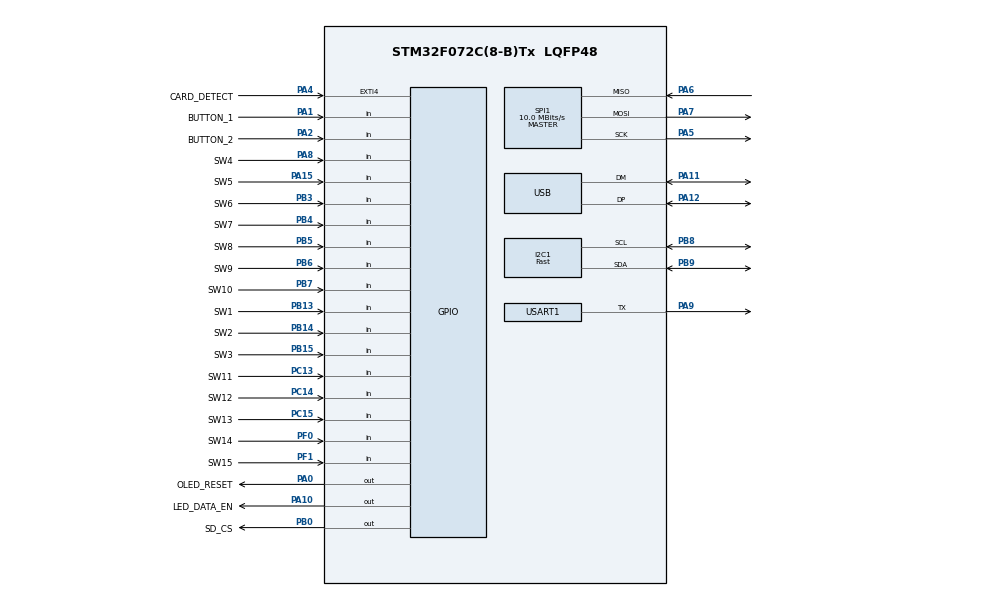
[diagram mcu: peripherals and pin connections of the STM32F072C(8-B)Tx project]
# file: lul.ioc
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FATFS._CODE_PAGE=1252
FATFS._FS_LOCK=0
FATFS._FS_NORTC=1
FATFS._FS_TINY=1
FATFS._LFN_UNICODE=0
FATFS._MAX_LFN=32
FATFS._USE_FIND=0
FATFS._USE_LFN=3
FATFS._USE_MKFS=0
FREERTOS.HEAP_NUMBER=1
FREERTOS.MEMORY_ALLOCATION=0
FREERTOS.Tasks01=kb_scan,0,256,kb_scan_task,Default,NULL,Dynamic,NULL,NULL
FREERTOS.configMINIMAL_STACK_SIZE=128
FREERTOS.configTOTAL_HEAP_SIZE=5100
I2C1.I2C_Speed_Mode=I2C_Fast
I2C1.Speed=400
I2C1.Timing=0x0000020B
IWDG.Prescaler=IWDG_PRESCALER_32
IWDG.Reload=4095
IWDG.Window=4095
Mcu.Family=STM32F0
Mcu.Name=STM32F072C(8-B)Tx
Mcu.Package=LQFP48
NVIC.EXTI4_15_IRQn=true\:3\:0\:false\:false\:true\:true\:true
NVIC.TIM6_DAC_IRQn=true\:0\:0\:false\:false\:true\:false\:true
NVIC.TimeBase=TIM6_DAC_IRQn
NVIC.TimeBaseIP=TIM6
NVIC.USB_IRQn=true\:3\:0\:false\:false\:true\:true\:true
PA0.GPIO_Label=OLED_RESET
PA0.PinState=GPIO_PIN_RESET
PA0.Signal=GPIO_Output
PA1.GPIO_Label=BUTTON_1
PA1.GPIO_PuPd=GPIO_PULLUP
PA1.Signal=GPIO_Input
PA10.GPIO_Label=LED_DATA_EN
PA10.Signal=GPIO_Output
PA11.Mode=Device
PA11.Signal=USB_DM
PA12.Mode=Device
PA12.Signal=USB_DP
PA13.Mode=Serial_Wire
PA13.Signal=SYS_SWDIO
PA14.Mode=Serial_Wire
PA14.Signal=SYS_SWCLK
PA15.GPIO_Label=SW5
PA15.GPIO_PuPd=GPIO_PULLUP
PA15.Signal=GPIO_Input
PA2.GPIO_Label=BUTTON_2
PA2.GPIO_PuPd=GPIO_PULLUP
PA2.Signal=GPIO_Input
PA4.GPIO_Label=CARD_DETECT
PA4.GPIO_ModeDefaultEXTI=GPIO_MODE_IT_RISING_FALLING
PA4.GPIO_PuPd=GPIO_PULLUP
PA4.Signal=GPXTI4
PA5.Mode=Full_Duplex_Master
PA5.Signal=SPI1_SCK
PA6.Mode=Full_Duplex_Master
PA6.Signal=SPI1_MISO
PA7.Mode=Full_Duplex_Master
PA7.Signal=SPI1_MOSI
PA8.GPIO_Label=SW4
PA8.GPIO_PuPd=GPIO_PULLUP
PA8.Signal=GPIO_Input
PA9.Mode=Half_duplex(single_wire_mode)
PA9.Signal=USART1_TX
PB0.GPIO_Label=SD_CS
PB0.GPIO_PuPd=GPIO_NOPULL
PB0.PinState=GPIO_PIN_SET
PB0.Signal=GPIO_Output
PB13.GPIO_Label=SW1
PB13.GPIO_PuPd=GPIO_PULLUP
PB13.Signal=GPIO_Input
PB14.GPIO_Label=SW2
PB14.GPIO_PuPd=GPIO_PULLUP
PB14.Signal=GPIO_Input
PB15.GPIO_Label=SW3
PB15.GPIO_PuPd=GPIO_PULLUP
PB15.Signal=GPIO_Input
PB3.GPIO_Label=SW6
PB3.GPIO_PuPd=GPIO_PULLUP
PB3.Signal=GPIO_Input
PB4.GPIO_Label=SW7
PB4.GPIO_PuPd=GPIO_PULLUP
PB4.Signal=GPIO_Input
PB5.GPIO_Label=SW8
PB5.GPIO_PuPd=GPIO_PULLUP
PB5.Signal=GPIO_Input
PB6.GPIO_Label=SW9
PB6.GPIO_PuPd=GPIO_PULLUP
PB6.Signal=GPIO_Input
PB7.GPIO_Label=SW10
PB7.GPIO_PuPd=GPIO_PULLUP
PB7.Signal=GPIO_Input
PB8.Mode=I2C
PB8.Signal=I2C1_SCL
PB9.Mode=I2C
PB9.Signal=I2C1_SDA
PC13.GPIO_Label=SW11
PC13.GPIO_PuPd=GPIO_PULLUP
PC13.Signal=GPIO_Input
PC14-OSC32_IN.GPIO_Label=SW12
PC14-OSC32_IN.GPIO_PuPd=GPIO_PULLUP
PC14-OSC32_IN.Signal=GPIO_Input
PC15-OSC32_OUT.GPIO_Label=SW13
PC15-OSC32_OUT.GPIO_PuPd=GPIO_PULLUP
PC15-OSC32_OUT.Signal=GPIO_Input
PF0-OSC_IN.GPIO_Label=SW14
PF0-OSC_IN.GPIO_PuPd=GPIO_PULLUP
PF0-OSC_IN.Signal=GPIO_Input
PF1-OSC_OUT.GPIO_Label=SW15
PF1-OSC_OUT.GPIO_PuPd=GPIO_PULLUP
PF1-OSC_OUT.Signal=GPIO_Input
ProjectManager.HeapSize=0x400
ProjectManager.StackSize=0x600
ProjectManager.TargetToolchain=MDK-ARM V5
RCC.AHBFreq_Value=40000000
RCC.APB1Freq_Value=40000000
RCC.APB1TimFreq_Value=40000000
RCC.HCLKFreq_Value=40000000
RCC.PLLMUL=RCC_PLL_MUL5
RCC.SYSCLKFreq_VALUE=40000000
RCC.SYSCLKSource=RCC_SYSCLKSOURCE_PLLCLK
RCC.Usart1ClockSelection=RCC_USART1CLKSOURCE_SYSCLK
SPI1.BaudRatePrescaler=SPI_BAUDRATEPRESCALER_4
SPI1.CalculateBaudRate=10.0 MBits/s
SPI1.DataSize=SPI_DATASIZE_8BIT
SPI1.Direction=SPI_DIRECTION_2LINES
SPI1.Mode=SPI_MODE_MASTER
SPI1.VirtualType=VM_MASTER
USART1.BaudRate=115200
USART1.Mode=MODE_TX
USART1.VirtualMode-Half_duplex(single_wire_mode)=VM_ASYNC
USART1.WordLength=WORDLENGTH_8B
USB_DEVICE.CLASS_NAME_FS=CUSTOMHID
USB_DEVICE.MANUFACTURER_STRING=dekuNukem
USB_DEVICE.PRODUCT_STRING_CUSTOMHID_FS=duckyPad(2020)
USB_DEVICE.VirtualMode=CustomHid
USB_DEVICE.VirtualModeFS=Custom_Hid_FS
VP_FATFS_VS_Generic.Mode=User_defined
VP_FREERTOS_VS_ENABLE.Mode=Enabled
VP_IWDG_VS_IWDG.Mode=IWDG_Activate
VP_SYS_VS_tim6.Mode=TIM6
VP_USB_DEVICE_VS_USB_DEVICE_CUSTOM_HID_FS.Mode=CUSTOM_HID_FS
board=lul

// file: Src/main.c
/**
  ******************************************************************************
  * @file           : main.c
  * @brief          : Main program body
  ******************************************************************************
  * This notice applies to any and all portions of this file
  * that are not between comment pairs USER CODE BEGIN and
  * USER CODE END. Other portions of this file, whether
  * inserted by the user or by software development tools
  * are owned by their respective copyright owners.
  *
  * Copyright (c) 2021 STMicroelectronics International N.V.
  * All rights reserved.
  *
  * Redistribution and use in source and binary forms, with or without
  * modification, are permitted, provided that the following conditions are met:
  *
  * 1. Redistribution of source code must retain the above copyright notice,
  *    this list of conditions and the following disclaimer.
  * 2. Redistributions in binary form must reproduce the above copyright notice,
  *    this list of conditions and the following disclaimer in the documentation
  *    and/or other materials provided with the distribution.
  * 3. Neither the name of STMicroelectronics nor the names of other
  *    contributors to this software may be used to endorse or promote products
  *    derived from this software without specific written permission.
  * 4. This software, including modifications and/or derivative works of this
  *    software, must execute solely and exclusively on microcontroller or
  *    microprocessor devices manufactured by or for STMicroelectronics.
  * 5. Redistribution and use of this software other than as permitted under
  *    this license is void and will automatically terminate your rights under
  *    this license.
  *
  * THIS SOFTWARE IS PROVIDED BY STMICROELECTRONICS AND CONTRIBUTORS "AS IS"
  * AND ANY EXPRESS, IMPLIED OR STATUTORY WARRANTIES, INCLUDING, BUT NOT
  * LIMITED TO, THE IMPLIED WARRANTIES OF MERCHANTABILITY, FITNESS FOR A
  * PARTICULAR PURPOSE AND NON-INFRINGEMENT OF THIRD PARTY INTELLECTUAL PROPERTY
  * RIGHTS ARE DISCLAIMED TO THE FULLEST EXTENT PERMITTED BY LAW. IN NO EVENT
  * SHALL STMICROELECTRONICS OR CONTRIBUTORS BE LIABLE FOR ANY DIRECT, INDIRECT,
  * INCIDENTAL, SPECIAL, EXEMPLARY, OR CONSEQUENTIAL DAMAGES (INCLUDING, BUT NOT
  * LIMITED TO, PROCUREMENT OF SUBSTITUTE GOODS OR SERVICES; LOSS OF USE, DATA,
  * OR PROFITS; OR BUSINESS INTERRUPTION) HOWEVER CAUSED AND ON ANY THEORY OF
  * LIABILITY, WHETHER IN CONTRACT, STRICT LIABILITY, OR TORT (INCLUDING
  * NEGLIGENCE OR OTHERWISE) ARISING IN ANY WAY OUT OF THE USE OF THIS SOFTWARE,
  * EVEN IF ADVISED OF THE POSSIBILITY OF SUCH DAMAGE.
  *
  ******************************************************************************
  */
#include "main.h"
#include "stm32f0xx_hal.h"
#include "cmsis_os.h"
#include "fatfs.h"
#include "usb_device.h"

/* USER CODE BEGIN Includes */
#include <stdio.h>
#include <string.h>
#include <stdlib.h>
#include "usbd_customhid.h"
#include "ssd1306.h"
#include "fonts.h"
#include "neopixel.h"
#include "buttons.h"
#include "keyboard.h"
#include "parser.h"
#include "shared.h"
#include "my_tasks.h"
#include "animations.h"

/* USER CODE END Includes */

I2C_HandleTypeDef hi2c1;

IWDG_HandleTypeDef hiwdg;

SPI_HandleTypeDef hspi1;

UART_HandleTypeDef huart1;

osThreadId kb_scanHandle;

/* USER CODE BEGIN PV */
/* Private variables ---------------------------------------------------------*/

/*
0.20.3 20221031
changed HOLD to EMUK

0.20.4 20221114
add JIS keys

0.21.0 20221117
changed USB HID descriptor so new japanese keys work

0.21.1 20221221
cleaned up animation code
tried out no animation at all, frees up about 1K of ram

0.21.2
massive overhaul to reduce RAM and ROM usage
using hashed lookup for string matching
new keymap select screen
reduced RTOS heap usage
cleaned up animation, much faster
no functional changes
mouse button not implemented yet

0.22.0 20230111
added mouse commands back
ready for public release

0.22.1 20230118
fixed a bug where STRING prints an extra space

1.0.0 20230202
beta release for duckyscript 3

1.1.0 20230214
added banked loading for large dsb files
cleaned up opcode values

1.1.1 20230215
fixed a bug where screen doesnt update when exiting keymap selection screen

1.1.2 20230221
added busy state

1.1.3 20230329
fixing a rand() bug where modulus power of 2 result in repeating patterns

1.1.4 20230409
fixed a SD card timing bug

1.2.0 20230502
ready for public release

1.2.1 20230630
fixed laggy EMUK
fixed EMUK-related n-key rollover bug
fixed pad crashing when changing profiles

1.3.0 20230701
added _TIME_S read-only variable

1.3.1
20231111
increased max profiles to 64
change MAX_PROFILES in parser.h
change BIN_BUF_SIZE in ds3_vm.c if out of space

1.3.2
2024 01 22
fixed backlight brightness saving bug

1.3.3
2024 12 02
Fixed non-responsive mouse scroll bug

1.3.4
2024 12 18
Fixed dead key behaviour
*/

uint8_t fw_version_major = 1;
uint8_t fw_version_minor = 3;
uint8_t fw_version_patch = 4;
char instruction[] = "For instructions, see";
/* USER CODE END PV */

void SystemClock_Config(void);
static void MX_GPIO_Init(void);
static void MX_USART1_UART_Init(void);
static void MX_SPI1_Init(void);
static void MX_I2C1_Init(void);
static void MX_IWDG_Init(void);
void kb_scan_task(void const * argument);
/* USER CODE BEGIN PFP */
/* Private function prototypes -----------------------------------------------*/

/* USER CODE END PFP */

/* USER CODE BEGIN 0 */
int fputc(int ch, FILE *f)
{
    HAL_UART_Transmit(&huart1, (unsigned char *)&ch, 1, 100);
    return ch;
}
/* USER CODE END 0 */

int main(void)
{

  /* MCU Configuration----------------------------------------------------------*/

  /* Reset of all peripherals, Initializes the Flash interface and the Systick. */
  HAL_Init();

  /* Configure the system clock */
  SystemClock_Config();

  /* Initialize all configured peripherals */
  MX_GPIO_Init();
  MX_USART1_UART_Init();
  MX_SPI1_Init();
  MX_I2C1_Init();
  MX_IWDG_Init();

  /* Create the thread(s) */
  /* definition and creation of kb_scan */
  osThreadDef(kb_scan, kb_scan_task, osPriorityNormal, 0, 256);
  kb_scanHandle = osThreadCreate(osThread(kb_scan), NULL);

  /* USER CODE BEGIN RTOS_THREADS */
  /* add threads, ... */
  // kb_scan_task should have 256 byte
  osThreadDef(keypress_task, keypress_task_start, osPriorityAboveNormal, 0, 512);
  osThreadCreate(osThread(keypress_task), NULL);
  /* USER CODE END RTOS_THREADS */

  /* Start scheduler */
  osKernelStart();

  /* We should never get here as control is now taken by the scheduler */

  /* Infinite loop */
  while (1)
  {

  }

}

void SystemClock_Config(void)
{

  RCC_OscInitTypeDef RCC_OscInitStruct;
  RCC_ClkInitTypeDef RCC_ClkInitStruct;
  RCC_PeriphCLKInitTypeDef PeriphClkInit;

    /**Initializes the CPU, AHB and APB busses clocks
    */
  RCC_OscInitStruct.OscillatorType = RCC_OSCILLATORTYPE_HSI|RCC_OSCILLATORTYPE_HSI48
                              |RCC_OSCILLATORTYPE_LSI;
  RCC_OscInitStruct.HSIState = RCC_HSI_ON;
  RCC_OscInitStruct.HSI48State = RCC_HSI48_ON;
  RCC_OscInitStruct.HSICalibrationValue = 16;
  RCC_OscInitStruct.LSIState = RCC_LSI_ON;
  RCC_OscInitStruct.PLL.PLLState = RCC_PLL_ON;
  RCC_OscInitStruct.PLL.PLLSource = RCC_PLLSOURCE_HSI;
  RCC_OscInitStruct.PLL.PLLMUL = RCC_PLL_MUL14;
  RCC_OscInitStruct.PLL.PREDIV = RCC_PREDIV_DIV3;
  if (HAL_RCC_OscConfig(&RCC_OscInitStruct) != HAL_OK)
  {
    _Error_Handler(__FILE__, __LINE__);
  }

    /**Initializes the CPU, AHB and APB busses clocks
    */
  RCC_ClkInitStruct.ClockType = RCC_CLOCKTYPE_HCLK|RCC_CLOCKTYPE_SYSCLK
                              |RCC_CLOCKTYPE_PCLK1;
  RCC_ClkInitStruct.SYSCLKSource = RCC_SYSCLKSOURCE_PLLCLK;
  RCC_ClkInitStruct.AHBCLKDivider = RCC_SYSCLK_DIV1;
  RCC_ClkInitStruct.APB1CLKDivider = RCC_HCLK_DIV1;

  if (HAL_RCC_ClockConfig(&RCC_ClkInitStruct, FLASH_LATENCY_1) != HAL_OK)
  {
    _Error_Handler(__FILE__, __LINE__);
  }

  PeriphClkInit.PeriphClockSelection = RCC_PERIPHCLK_USB|RCC_PERIPHCLK_USART1
                              |RCC_PERIPHCLK_I2C1;
  PeriphClkInit.Usart1ClockSelection = RCC_USART1CLKSOURCE_SYSCLK;
  PeriphClkInit.I2c1ClockSelection = RCC_I2C1CLKSOURCE_HSI;
  PeriphClkInit.UsbClockSelection = RCC_USBCLKSOURCE_HSI48;

  if (HAL_RCCEx_PeriphCLKConfig(&PeriphClkInit) != HAL_OK)
  {
    _Error_Handler(__FILE__, __LINE__);
  }

    /**Configure the Systick interrupt time
    */
  HAL_SYSTICK_Config(HAL_RCC_GetHCLKFreq()/1000);

    /**Configure the Systick
    */
  HAL_SYSTICK_CLKSourceConfig(SYSTICK_CLKSOURCE_HCLK);

  /* SysTick_IRQn interrupt configuration */
  HAL_NVIC_SetPriority(SysTick_IRQn, 3, 0);
}

/* I2C1 init function */
static void MX_I2C1_Init(void)
{

  hi2c1.Instance = I2C1;
  hi2c1.Init.Timing = 0x0000020B;
  hi2c1.Init.OwnAddress1 = 0;
  hi2c1.Init.AddressingMode = I2C_ADDRESSINGMODE_7BIT;
  hi2c1.Init.DualAddressMode = I2C_DUALADDRESS_DISABLE;
  hi2c1.Init.OwnAddress2 = 0;
  hi2c1.Init.OwnAddress2Masks = I2C_OA2_NOMASK;
  hi2c1.Init.GeneralCallMode = I2C_GENERALCALL_DISABLE;
  hi2c1.Init.NoStretchMode = I2C_NOSTRETCH_DISABLE;
  if (HAL_I2C_Init(&hi2c1) != HAL_OK)
  {
    _Error_Handler(__FILE__, __LINE__);
  }

    /**Configure Analogue filter
    */
  if (HAL_I2CEx_ConfigAnalogFilter(&hi2c1, I2C_ANALOGFILTER_ENABLE) != HAL_OK)
  {
    _Error_Handler(__FILE__, __LINE__);
  }

    /**Configure Digital filter
    */
  if (HAL_I2CEx_ConfigDigitalFilter(&hi2c1, 0) != HAL_OK)
  {
    _Error_Handler(__FILE__, __LINE__);
  }

}

/* IWDG init function */
static void MX_IWDG_Init(void)
{

  hiwdg.Instance = IWDG;
  hiwdg.Init.Prescaler = IWDG_PRESCALER_32;
  hiwdg.Init.Window = 4095;
  hiwdg.Init.Reload = 4095;
  if (HAL_IWDG_Init(&hiwdg) != HAL_OK)
  {
    _Error_Handler(__FILE__, __LINE__);
  }

}

/* SPI1 init function */
static void MX_SPI1_Init(void)
{

  /* SPI1 parameter configuration*/
  hspi1.Instance = SPI1;
  hspi1.Init.Mode = SPI_MODE_MASTER;
  hspi1.Init.Direction = SPI_DIRECTION_2LINES;
  hspi1.Init.DataSize = SPI_DATASIZE_8BIT;
  hspi1.Init.CLKPolarity = SPI_POLARITY_LOW;
  hspi1.Init.CLKPhase = SPI_PHASE_1EDGE;
  hspi1.Init.NSS = SPI_NSS_SOFT;
  hspi1.Init.BaudRatePrescaler = SPI_BAUDRATEPRESCALER_4;
  hspi1.Init.FirstBit = SPI_FIRSTBIT_MSB;
  hspi1.Init.TIMode = SPI_TIMODE_DISABLE;
  hspi1.Init.CRCCalculation = SPI_CRCCALCULATION_DISABLE;
  hspi1.Init.CRCPolynomial = 7;
  hspi1.Init.CRCLength = SPI_CRC_LENGTH_DATASIZE;
  hspi1.Init.NSSPMode = SPI_NSS_PULSE_ENABLE;
  if (HAL_SPI_Init(&hspi1) != HAL_OK)
  {
    _Error_Handler(__FILE__, __LINE__);
  }

}

/* USART1 init function */
static void MX_USART1_UART_Init(void)
{

  huart1.Instance = USART1;
  huart1.Init.BaudRate = 115200;
  huart1.Init.WordLength = UART_WORDLENGTH_8B;
  huart1.Init.StopBits = UART_STOPBITS_1;
  huart1.Init.Parity = UART_PARITY_NONE;
  huart1.Init.Mode = UART_MODE_TX;
  huart1.Init.HwFlowCtl = UART_HWCONTROL_NONE;
  huart1.Init.OverSampling = UART_OVERSAMPLING_16;
  huart1.Init.OneBitSampling = UART_ONE_BIT_SAMPLE_DISABLE;
  huart1.AdvancedInit.AdvFeatureInit = UART_ADVFEATURE_NO_INIT;
  if (HAL_HalfDuplex_Init(&huart1) != HAL_OK)
  {
    _Error_Handler(__FILE__, __LINE__);
  }

}

/** Configure pins as
        * Analog
        * Input
        * Output
        * EVENT_OUT
        * EXTI
*/
static void MX_GPIO_Init(void)
{

  GPIO_InitTypeDef GPIO_InitStruct;

  /* GPIO Ports Clock Enable */
  __HAL_RCC_GPIOC_CLK_ENABLE();
  __HAL_RCC_GPIOF_CLK_ENABLE();
  __HAL_RCC_GPIOA_CLK_ENABLE();
  __HAL_RCC_GPIOB_CLK_ENABLE();

  /*Configure GPIO pin Output Level */
  HAL_GPIO_WritePin(GPIOA, OLED_RESET_Pin|LED_DATA_EN_Pin, GPIO_PIN_RESET);

  /*Configure GPIO pin Output Level */
  HAL_GPIO_WritePin(SD_CS_GPIO_Port, SD_CS_Pin, GPIO_PIN_SET);

  /*Configure GPIO pins : SW11_Pin SW12_Pin SW13_Pin */
  GPIO_InitStruct.Pin = SW11_Pin|SW12_Pin|SW13_Pin;
  GPIO_InitStruct.Mode = GPIO_MODE_INPUT;
  GPIO_InitStruct.Pull = GPIO_PULLUP;
  HAL_GPIO_Init(GPIOC, &GPIO_InitStruct);

  /*Configure GPIO pins : SW14_Pin SW15_Pin */
  GPIO_InitStruct.Pin = SW14_Pin|SW15_Pin;
  GPIO_InitStruct.Mode = GPIO_MODE_INPUT;
  GPIO_InitStruct.Pull = GPIO_PULLUP;
  HAL_GPIO_Init(GPIOF, &GPIO_InitStruct);

  /*Configure GPIO pins : OLED_RESET_Pin LED_DATA_EN_Pin */
  GPIO_InitStruct.Pin = OLED_RESET_Pin|LED_DATA_EN_Pin;
  GPIO_InitStruct.Mode = GPIO_MODE_OUTPUT_PP;
  GPIO_InitStruct.Pull = GPIO_NOPULL;
  GPIO_InitStruct.Speed = GPIO_SPEED_FREQ_LOW;
  HAL_GPIO_Init(GPIOA, &GPIO_InitStruct);

  /*Configure GPIO pins : BUTTON_1_Pin BUTTON_2_Pin SW4_Pin SW5_Pin */
  GPIO_InitStruct.Pin = BUTTON_1_Pin|BUTTON_2_Pin|SW4_Pin|SW5_Pin;
  GPIO_InitStruct.Mode = GPIO_MODE_INPUT;
  GPIO_InitStruct.Pull = GPIO_PULLUP;
  HAL_GPIO_Init(GPIOA, &GPIO_InitStruct);

  /*Configure GPIO pin : CARD_DETECT_Pin */
  GPIO_InitStruct.Pin = CARD_DETECT_Pin;
  GPIO_InitStruct.Mode = GPIO_MODE_IT_RISING_FALLING;
  GPIO_InitStruct.Pull = GPIO_PULLUP;
  HAL_GPIO_Init(CARD_DETECT_GPIO_Port, &GPIO_InitStruct);

  /*Configure GPIO pin : SD_CS_Pin */
  GPIO_InitStruct.Pin = SD_CS_Pin;
  GPIO_InitStruct.Mode = GPIO_MODE_OUTPUT_PP;
  GPIO_InitStruct.Pull = GPIO_NOPULL;
  GPIO_InitStruct.Speed = GPIO_SPEED_FREQ_LOW;
  HAL_GPIO_Init(SD_CS_GPIO_Port, &GPIO_InitStruct);

  /*Configure GPIO pins : SW1_Pin SW2_Pin SW3_Pin SW6_Pin
                           SW7_Pin SW8_Pin SW9_Pin SW10_Pin */
  GPIO_InitStruct.Pin = SW1_Pin|SW2_Pin|SW3_Pin|SW6_Pin
                          |SW7_Pin|SW8_Pin|SW9_Pin|SW10_Pin;
  GPIO_InitStruct.Mode = GPIO_MODE_INPUT;
  GPIO_InitStruct.Pull = GPIO_PULLUP;
  HAL_GPIO_Init(GPIOB, &GPIO_InitStruct);

  /* EXTI interrupt init*/
  HAL_NVIC_SetPriority(EXTI4_15_IRQn, 3, 0);
  HAL_NVIC_EnableIRQ(EXTI4_15_IRQn);

}

/* USER CODE BEGIN 4 */
void HAL_GPIO_EXTI_Callback(uint16_t GPIO_Pin)
{
  HAL_Delay(200);
  NVIC_SystemReset();
}

/* USER CODE END 4 */

void kb_scan_task(void const * argument)
{
  /* init code for FATFS */
  MX_FATFS_Init();

  /* init code for USB_DEVICE */
  MX_USB_DEVICE_Init();

  /* USER CODE BEGIN 5 */
  neopixel_off();
  uint8_t mount_result = f_mount(&sd_fs, "", 1);
  HAL_GPIO_WritePin(OLED_RESET_GPIO_Port, OLED_RESET_Pin, GPIO_PIN_RESET);
  osDelay(10);
  HAL_GPIO_WritePin(OLED_RESET_GPIO_Port, OLED_RESET_Pin, GPIO_PIN_SET);
  osDelay(20);
  ssd1306_Init();
  ssd1306_Fill(Black);

  if(mount_result)
  {
    ssd1306_Fill(Black);
    ssd1306_SetCursor(0, 5);
    ssd1306_WriteString("Please Insert SD Card",Font_6x10,White);

    memset(temp_buf, 0, PATH_SIZE);
    sprintf(temp_buf, "FW V%d.%d.%d", fw_version_major, fw_version_minor, fw_version_patch);
    ssd1306_SetCursor(35, 52);
    ssd1306_WriteString(temp_buf,Font_6x10,White);

    ssd1306_SetCursor(0, 22);
    ssd1306_WriteString(instruction,Font_6x10,White);
    ssd1306_SetCursor(24, 35);
    ssd1306_WriteString(project_url,Font_6x10,White);
    ssd1306_UpdateScreen();
    while(1)
    {
      HAL_IWDG_Refresh(&hiwdg);
      osDelay(30);
    }
  }

  load_settings();
  scan_profiles();
  // this line must be after scan_profiles()
  uint8_t last_profile = get_last_profile();
  if(last_profile == 0)
    change_profile(NEXT_PROFILE);
  else
    restore_profile(last_profile);

  init_complete = 1;
  /* Infinite loop */
  printf("fhs: %u\n", xPortGetFreeHeapSize());
  anime_init();
  for(;;)
  {
    HAL_IWDG_Refresh(&hiwdg);
    keyboard_update();
    animation_task_start();
    osDelay(16);
  }
  /* USER CODE END 5 */
}

void HAL_TIM_PeriodElapsedCallback(TIM_HandleTypeDef *htim)
{
  if (htim->Instance == TIM6) {
    HAL_IncTick();
  }
}

void _Error_Handler(char *file, int line)
{
  while(1)
  {
  }
}

/************************ (C) COPYRIGHT STMicroelectronics *****END OF FILE****/
